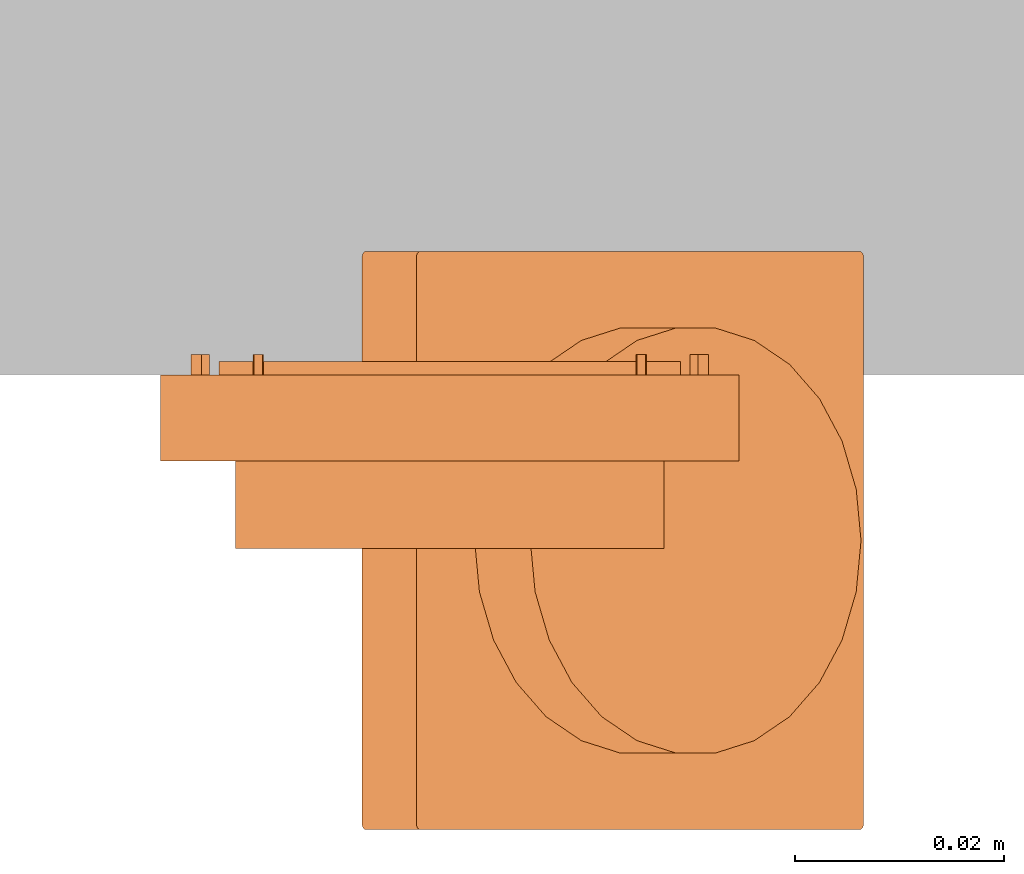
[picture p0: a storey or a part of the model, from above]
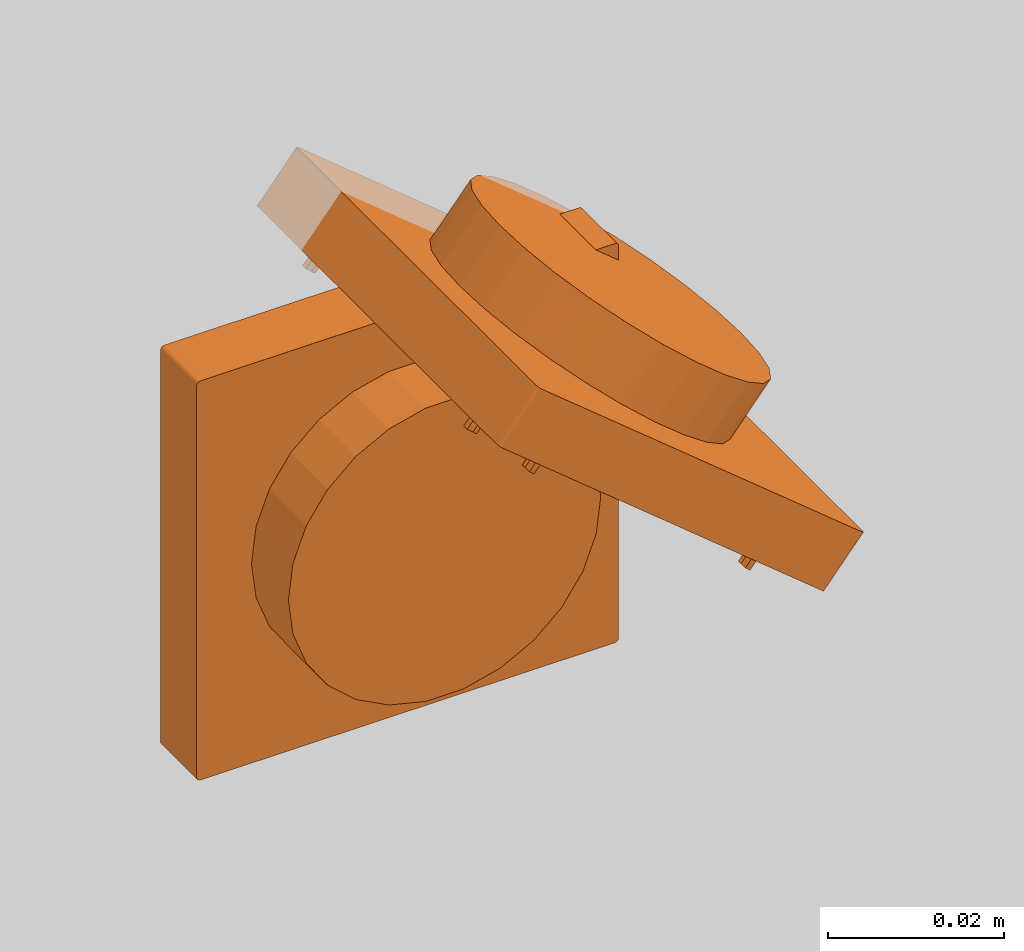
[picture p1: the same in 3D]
Properties of the parts of a building model (IFC2X3)

# File
Description: ViewDefinition [CoordinationView_V2.0]
File name: Projektnummer
Time: 2019-08-29T11:54:56
Written by: The EXPRESS Data Manager Version 5.02.0100.07 : 28 Aug 2013
Made in: 20160225_1515(x64) - Exporter 17.0.416.0 - Alternate UI 17.12.14.0
Comment: STEP Physical File produced by: The EXPRESS Data Manager Version 5.02.0100.07 : 28 Aug 2013 * Module: EDMstepFileFactory/EDMstandAlone * Creation date: Thu Aug 29 11:54:56 2019 * Host: B-BIM-NB-4736 * Database: C:\Users\Enkler\AppData\Local\Temp\{734C23E3-BAEC-49E9-B487-1169E46ECDAC}\ifc * Database version: 5507 * Database creation date: Thu Aug 29 11:54:54 2019 * Schema: IFC2X3 * Model: DataRepository.ifc * Model creation date: Thu Aug 29 11:54:54 2019 * Header model: DataRepository.ifc_HeaderModel * Header model creation date: Thu Aug 29 11:54:54 2019 * EDMuser: sdai-user * EDMgroup: sdai-group * License ID and type: 5605 : Permanent license. Expiry date: * EDMstepFileFactory options: 020000

# IfcProject, Projektnummer
LongName: Projektname; Phase: Projektstatus

# IfcSite, Default
RefLatitude: 52, 30, 59, 765625; RefLongitude: 13, 23, 59, 998626; RefElevation: 0 m
Sonstige - Kategorie: Projektinformationen; Kundenname: Bauherr; Projektadresse: Projektadresse; Projektausgabedatum: Projekt Datum; Projektname: Projektname; Projektnummer: Projektnummer; Projektstatus: Projektstatus; Verfasser eMail: E-Mail; Verfasser Firma 1: Firma 1; Verfasser Firma 2: Firma 2; Verfasser PLZ Ort: PLZ Ort; Verfasser Strasse: Strasse; Verfasser Telefax: Telefax; Verfasser Telefon: Telefon

# IfcBuilding
Pset_BuildingCommon - NumberOfStoreys: 1
Sonstige - Kategorie: Projektinformationen; Kundenname: Bauherr; Projektadresse: Projektadresse; Projektausgabedatum: Projekt Datum; Projektname: Projektname; Projektnummer: Projektnummer; Projektstatus: Projektstatus; Verfasser eMail: E-Mail; Verfasser Firma 1: Firma 1; Verfasser Firma 2: Firma 2; Verfasser PLZ Ort: PLZ Ort; Verfasser Strasse: Strasse; Verfasser Telefax: Telefax; Verfasser Telefon: Telefon

# IfcBuildingStorey, Ebene 0
LongName: Ebene 0; Elevation: 0 m
Sonstige - Kategorie: Ebenen; Familienname: Ebene; Familie: Ebene: Ebene; Familie und Typ: Ebene: Ebene; Typ: Ebene: Ebene; Typ-ID: Ebene: Ebene
ID-Daten - Typname: Ebene; Tragwerk: no; Gebäudegeschoss: yes; Name: Ebene 0
Grafiken - Farbe: 16711680; Linienmuster: Verdeckt; Linienstärke: 1; Symbol: Beschriftung Ebene: Beschriftung Ebene; Symbol bei Ende 1 Standard: no; Symbol bei Ende 2 Standard: yes
Abhängigkeiten - Basishöhe: Projekt-Basispunkt; Ansicht: 0 m
Abmessungen - Höhe für Berechnung: 0 m

# IfcBuildingElementProxy: GIRA_065227_ENG (2)
In: Ebene 0
Type - Material: White
Type - Abhängigkeiten - Vorgabe-Ansicht: 1.2192 m
Type - Allgemein - Colour Text: White; Halogen free: yes; HeinzeBIM: https://www.heinze.de/bim/cov-knob-speed-regul-system-55-p-white-m/9694cc4a643f7b08fb017943ff4f762f2061f36f; Imprint/indication: Symbol "rotational speed"; Material: Plastic; Material quality: Thermoplastic; Model Text: Turn button; Suitable for degree of protection (IP): IP20; Surface finishing: Matt; Surface protection: Other; Type of fastening: Screw mounting
Type - Daten - RAL-number (akin): 9010
Type - ID-Daten - Beschreibung: Cov.knob speed reg. Sys55 PWm,Cover with knob for speed regulator,,pure white matt,; GTIN: 4010337652274; HAN: 065227; Hersteller: Gira; Typname: GIRA_065227_ENG; URL: https://www.gira.de/
Type - Sonstige - Kategorie: Elektroinstallationen; Familienname: GIRA_065227_ENG
Pset_BuildingElementProxyCommon - Reference: GIRA_065227_ENG
Pset_ManufacturerTypeInformation - Manufacturer: Gira
Abhängigkeiten - Ebene: Ebene: Ebene 0
Abmessungen - Fläche: 0.00513004 m2; Volumen: 0.0000570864 m3
Elektro - Stromkreise - Elektrische Daten: 220 V/1-0 VA
Phasen - Phase erstellt: Phase 1
Sonstige - Bauteillistenebene: Ebene: Ebene 0; Familie: GIRA_065227_ENG: GIRA_065227_ENG; Familie und Typ: GIRA_065227_ENG: GIRA_065227_ENG; Typ: GIRA_065227_ENG: GIRA_065227_ENG; Typ-ID: GIRA_065227_ENG: GIRA_065227_ENG
Name (GIRA_065227_ENG:GIRA_065227_ENG:...) | Basisbauteil | Erhebung (m) | Kennzeichen
389624 | Basiswand : MW 24.0 WD 12.0 | 1.50687 | 1
389647 | GIRA_065227_ENG : GIRA_065227_ENG | 1.52271 | 2

# IfcWallStandardCase: Basiswand:MW 24.0 WD 12.0, Basiswand:MW 24.0 WD 12.0:388646
In: Ebene 0
Type - PredefinedType: STANDARD; Material: Wärmedämmung - hart 0.12 m, Mauerwerk - Ziegel, verputzt 0.24 m
Type - Analytische Eigenschaften - Absorptionsgrad: 0.7; Rauigkeit: 3; Thermischer Widerstand (R): 3.87302; Thermisch wirksame Masse: 316537; Wärmeübergangskoeffizient (U): 0.258197
Type - Grafiken - Farbfüllung für groben Maßstab: 0; Füllmuster für groben Maßstab: Standard - Füllung
Type - ID-Daten - Beschreibung: Mauerwerk 24.0 cm, Wärmedämmung 12.0 cm; Typenkommentare: Mehrschaliges Mauerwerk; Typname: MW 24.0 WD 12.0
Type - Konstruktion - Abschluss an Öffnungen: Keine; Abschluss an Wänden: Keine; Breite: 0.36 m; Funktion: Außen
Type - Materialien und Oberflächen - Tragendes Material: Mauerwerk - Ziegel, verputzt
Type - Sonstige - Kategorie: Wände; Familienname: Basiswand
Abhängigkeiten - Abhängigkeit oben: Ebene: Ebene 1; Abhängigkeit unten: Ebene: Ebene 0; Basislinie: Wandachse; Für Körper: no; Nicht verknüpfte Höhe: 3 m; Oberkante ist fixiert.: no; Raumbegrenzung: yes; Unterkante ist fixiert: no; Verlängerungsabstand oben: 0 m; Verlängerungsabstand unten: 0 m; Versatz oben: 0 m; Versatz unten: 0 m
Abmessungen - Fläche: 9 m2; Länge: 3 m; Volumen: 3.24 m3
Phasen - Phase erstellt: Phase 1
Sonstige - Familie: Basiswand: MW 24.0 WD 12.0; Familie und Typ: Basiswand: MW 24.0 WD 12.0; Typ: Basiswand: MW 24.0 WD 12.0; Typ-ID: Basiswand: MW 24.0 WD 12.0
Tragwerk - Berechnungsmodell aktivieren: no; Tragwerk: no; Tragwerksverwendung: Nichttragend
Pset_WallCommon - Reference: MW 24.0 WD 12.0; LoadBearing: no; ExtendToStructure: no; IsExternal: yes; ThermalTransmittance: 0.258197 kg/K/s3
